VERSION 5.8 ;
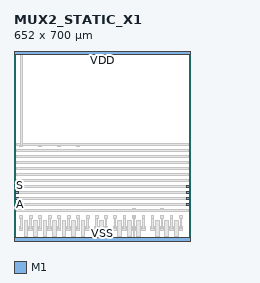
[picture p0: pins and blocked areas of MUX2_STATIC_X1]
MACRO MUX2_STATIC_X1
  CLASS CORE ;
  ORIGIN 0 0 ;
  SIZE 652 BY 700 ;
  SITE ICPS2023_5_ROW700 ;
  PIN A
    DIRECTION INPUT ;
    USE SIGNAL ;
    PORT
      LAYER M1 ;
        RECT 5 130 15 140 ;
        RECT 637 130 647 140 ;
    END
  END A
  PIN B
    DIRECTION INPUT ;
    USE SIGNAL ;
    PORT
      LAYER M1 ;
        RECT 5 152 15 162 ;
        RECT 637 152 647 162 ;
    END
  END B
  PIN S
    DIRECTION INPUT ;
    USE SIGNAL ;
    PORT
      LAYER M1 ;
        RECT 5 174 15 184 ;
        RECT 637 174 647 184 ;
    END
  END S
  PIN Y
    DIRECTION OUTPUT ;
    USE SIGNAL ;
    PORT
      LAYER M1 ;
        RECT 5 196 15 206 ;
        RECT 637 196 647 206 ;
    END
  END Y
  PIN VDD
    DIRECTION INOUT ;
    USE POWER ;
    PORT
      LAYER M1 ;
        RECT 0 688 652 700 ;
    END
  END VDD
  PIN VSS
    DIRECTION INOUT ;
    USE GROUND ;
    PORT
      LAYER M1 ;
        RECT 0 0 652 12 ;
    END
  END VSS
  OBS
    LAYER M1 ;
      RECT 20 39.5 33 52.5 ;
      RECT 55 39.5 68 52.5 ;
      RECT 90 39.5 103 52.5 ;
      RECT 125 39.5 138 52.5 ;
      RECT 160 39.5 173 52.5 ;
      RECT 195 39.5 208 52.5 ;
      RECT 230 39.5 243 52.5 ;
      RECT 265 39.5 278 52.5 ;
      RECT 37.5 16 50.5 29 ;
      RECT 37.5 63 50.5 76 ;
      RECT 37 16 51 76 ;
      RECT 72.5 16 85.5 29 ;
      RECT 72.5 63 85.5 76 ;
      RECT 72 16 86 76 ;
      RECT 107.5 16 120.5 29 ;
      RECT 107.5 63 120.5 76 ;
      RECT 107 16 121 76 ;
      RECT 142.5 16 155.5 29 ;
      RECT 142.5 63 155.5 76 ;
      RECT 142 16 156 76 ;
      RECT 177.5 16 190.5 29 ;
      RECT 177.5 63 190.5 76 ;
      RECT 177 16 191 76 ;
      RECT 212.5 16 225.5 29 ;
      RECT 212.5 63 225.5 76 ;
      RECT 212 16 226 76 ;
      RECT 247.5 16 260.5 29 ;
      RECT 247.5 63 260.5 76 ;
      RECT 247 16 261 76 ;
      RECT 23.5 46 29.5 89 ;
      RECT 21.5 84 31.5 94 ;
      RECT 21.5 350 31.5 360 ;
      RECT 58.5 46 64.5 89 ;
      RECT 56.5 84 66.5 94 ;
      RECT 56.5 196 66.5 206 ;
      RECT 93.5 46 99.5 89 ;
      RECT 91.5 84 101.5 94 ;
      RECT 91.5 350 101.5 360 ;
      RECT 128.5 46 134.5 89 ;
      RECT 126.5 84 136.5 94 ;
      RECT 126.5 328 136.5 338 ;
      RECT 163.5 46 169.5 89 ;
      RECT 161.5 84 171.5 94 ;
      RECT 161.5 350 171.5 360 ;
      RECT 198.5 46 204.5 89 ;
      RECT 196.5 84 206.5 94 ;
      RECT 196.5 306 206.5 316 ;
      RECT 233.5 46 239.5 89 ;
      RECT 231.5 84 241.5 94 ;
      RECT 231.5 350 241.5 360 ;
      RECT 268.5 46 274.5 89 ;
      RECT 266.5 84 276.5 94 ;
      RECT 266.5 284 276.5 294 ;
      RECT 39 328 49 338 ;
      RECT 74 306 84 316 ;
      RECT 109 284 119 294 ;
      RECT 144 152 154 162 ;
      RECT 179 174 189 184 ;
      RECT 214 130 224 140 ;
      RECT 249 174 259 184 ;
      RECT 298 39.5 311 52.5 ;
      RECT 333 39.5 346 52.5 ;
      RECT 315.5 16 328.5 29 ;
      RECT 315.5 63 328.5 76 ;
      RECT 315 16 329 76 ;
      RECT 301.5 46 307.5 89 ;
      RECT 299.5 84 309.5 94 ;
      RECT 299.5 218 309.5 228 ;
      RECT 336.5 46 342.5 89 ;
      RECT 334.5 84 344.5 94 ;
      RECT 334.5 306 344.5 316 ;
      RECT 317 130 327 140 ;
      RECT 366 39.5 379 52.5 ;
      RECT 401 39.5 414 52.5 ;
      RECT 436 39.5 449 52.5 ;
      RECT 471 39.5 484 52.5 ;
      RECT 383.5 16 396.5 29 ;
      RECT 383.5 63 396.5 76 ;
      RECT 383 16 397 76 ;
      RECT 418.5 16 431.5 29 ;
      RECT 418.5 63 431.5 76 ;
      RECT 418 16 432 76 ;
      RECT 453.5 16 466.5 29 ;
      RECT 453.5 63 466.5 76 ;
      RECT 453 16 467 76 ;
      RECT 369.5 46 375.5 89 ;
      RECT 367.5 84 377.5 94 ;
      RECT 367.5 196 377.5 206 ;
      RECT 404.5 46 410.5 89 ;
      RECT 402.5 84 412.5 94 ;
      RECT 402.5 262 412.5 272 ;
      RECT 439.5 46 445.5 89 ;
      RECT 437.5 84 447.5 94 ;
      RECT 437.5 108 447.5 118 ;
      RECT 474.5 46 480.5 89 ;
      RECT 472.5 84 482.5 94 ;
      RECT 472.5 284 482.5 294 ;
      RECT 385 306 395 316 ;
      RECT 420 328 430 338 ;
      RECT 455 174 465 184 ;
      RECT 504 39.5 517 52.5 ;
      RECT 539 39.5 552 52.5 ;
      RECT 574 39.5 587 52.5 ;
      RECT 609 39.5 622 52.5 ;
      RECT 521.5 16 534.5 29 ;
      RECT 521.5 63 534.5 76 ;
      RECT 521 16 535 76 ;
      RECT 556.5 16 569.5 29 ;
      RECT 556.5 63 569.5 76 ;
      RECT 556 16 570 76 ;
      RECT 591.5 16 604.5 29 ;
      RECT 591.5 63 604.5 76 ;
      RECT 591 16 605 76 ;
      RECT 507.5 46 513.5 89 ;
      RECT 505.5 84 515.5 94 ;
      RECT 505.5 218 515.5 228 ;
      RECT 542.5 46 548.5 89 ;
      RECT 540.5 84 550.5 94 ;
      RECT 540.5 108 550.5 118 ;
      RECT 577.5 46 583.5 89 ;
      RECT 575.5 84 585.5 94 ;
      RECT 575.5 240 585.5 250 ;
      RECT 612.5 46 618.5 89 ;
      RECT 610.5 84 620.5 94 ;
      RECT 610.5 328 620.5 338 ;
      RECT 523 174 533 184 ;
      RECT 558 284 568 294 ;
      RECT 593 152 603 162 ;
      RECT 10 110 642 116 ;
      RECT 10 132 642 138 ;
      RECT 10 154 642 160 ;
      RECT 10 176 642 182 ;
      RECT 10 198 642 204 ;
      RECT 10 220 642 226 ;
      RECT 10 242 642 248 ;
      RECT 10 264 642 270 ;
      RECT 10 286 642 292 ;
      RECT 10 308 642 314 ;
      RECT 10 330 642 336 ;
      RECT 10 352 642 358 ;
      RECT 439.5 3 445.5 92 ;
      RECT 23.5 352 29.5 697 ;
  END
END MUX2_STATIC_X1
